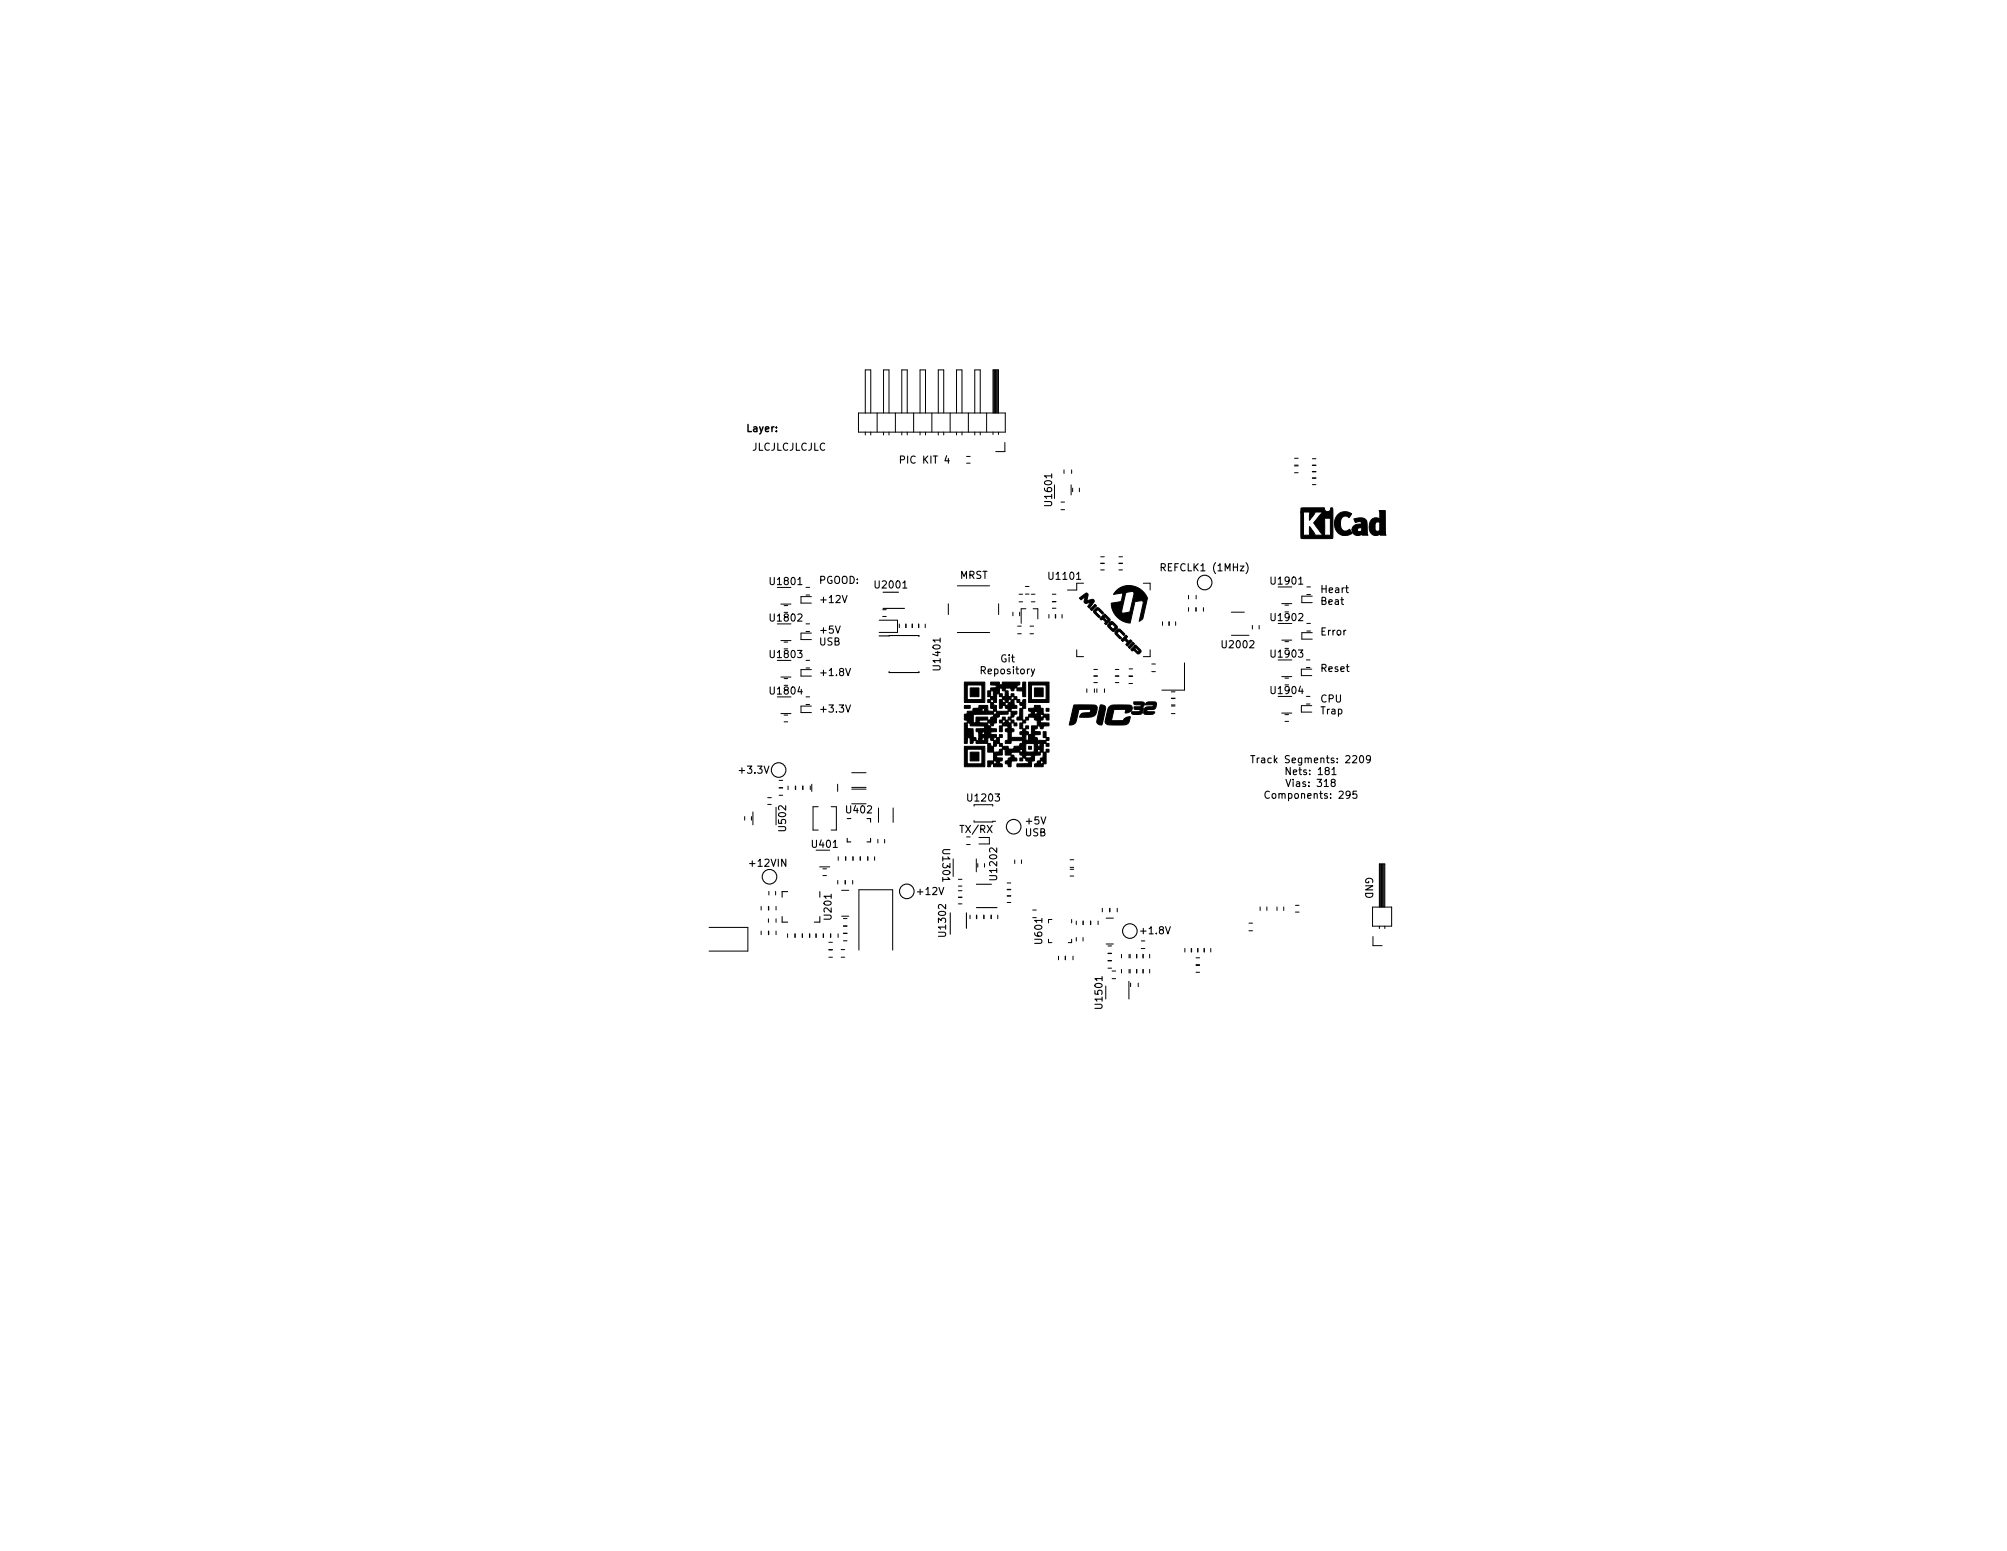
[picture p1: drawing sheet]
<svg xmlns="http://www.w3.org/2000/svg" width="279mm" height="216mm" viewBox="0 0 279 216" stroke-linecap="round" stroke-linejoin="round" font-family="sans-serif">
<defs><g id="words">
<g font-size="1.4">
<text x="104" y="60.1">Layer:</text>
<text x="104.6" y="62.7">JLCJLCJLCJLC</text>
<text x="125.7" y="64.5">PIC KIT 4</text>
<text x="146.5" y="70.2" transform="rotate(-90 146.5 70.2)">U1601</text>
<text x="107.4" y="81.4">U1801</text>
<text x="113.9" y="81.3">PGOOD:</text>
<text x="113.9" y="83.9">+12V</text>
<text x="122" y="81.9">U2001</text>
<text x="133.6" y="80.6">MRST</text>
<text x="146.2" y="80.7">U1101</text>
<text x="162" y="79.5">REFCLK1 (1MHz)</text>
<text x="177.1" y="81.4">U1901</text>
<text x="183.7" y="82.5">Heart</text>
<text x="107.4" y="86.5">U1802</text>
<text x="113.9" y="88.2">+5V</text>
<text x="113.9" y="89.8">USB</text>
<text x="177.1" y="86.4">U1902</text>
<text x="183.7" y="88.4">Error</text>
<text x="183.7" y="84.2">Beat</text>
<text x="107.4" y="91.6">U1803</text>
<text x="113.9" y="94.1">+1.8V</text>
<text x="130.9" y="93.1" transform="rotate(-90 130.9 93.1)">U1401</text>
<text x="136.6" y="93.8">Repository</text>
<text x="139.3" y="92.2">Git</text>
<text x="170.3" y="90.2">U2002</text>
<text x="177.1" y="91.5">U1903</text>
<text x="183.7" y="93.5">Reset</text>
<text x="107.4" y="96.7">U1804</text>
<text x="113.9" y="99.2">+3.3V</text>
<text x="177.1" y="96.6">U1904</text>
<text x="183.7" y="97.8">CPU</text>
<text x="183.7" y="99.4">Trap</text>
<text x="103.1" y="107.7">+3.3V</text>
<text x="175.1" y="106.2">Track Segments: 2209</text>
<text x="179.4" y="107.9">Nets: 181</text>
<text x="117.9" y="113.2">U402</text>
<text x="134.9" y="111.6">U1203</text>
<text x="176.7" y="111.2">Components: 295</text>
<text x="179.5" y="109.5">Vias: 318</text>
<text x="109.4" y="115.6" transform="rotate(-90 109.4 115.6)">U502</text>
<text x="113.1" y="118">U401</text>
<text x="131.2" y="118.4" transform="rotate(90 131.2 118.4)">U1301</text>
<text x="133.8" y="115.9">TX/RX</text>
<text x="142.7" y="116.4">USB</text>
<text x="142.9" y="114.8">+5V</text>
<text x="104.5" y="120.6">+12VIN</text>
<text x="127.8" y="124.6">+12V</text>
<text x="138.8" y="122.3" transform="rotate(-90 138.8 122.3)">U1202</text>
<text x="190.1" y="122" transform="rotate(90 190.1 122)">GND</text>
<text x="115.8" y="127.9" transform="rotate(-90 115.8 127.9)">U201</text>
<text x="131.7" y="130.2" transform="rotate(-90 131.7 130.2)">U1302</text>
<text x="145.1" y="131.3" transform="rotate(-90 145.1 131.3)">U601</text>
<text x="158.9" y="130">+1.8V</text>
<text x="153.5" y="140.2" transform="rotate(-90 153.5 140.2)">U1501</text>
</g>
</g></defs>
<g fill="none" stroke="#000" stroke-width=".15">
<path d="M116.3 87.1l.3 1 .4-1M117.3 82.9l.3 1 .3-1M117.7 93l.4 1 .3-1M117.7 98.1l.4 1 .3-1M122.4 88.5h5.5v.1M122.9 84.7h3M122.9 82.4h2.2M123.8 93.5v.1h4.1v-.1M117.9 116.7v.5h.5M117.9 113.9h.5M120.7 113.9h.5v.5M121.2 116.7v.5h-.5"/>
<path d="M174.1 105.2h.6M174.4 105.2v1M176.7 110.2a.47 .47 0 0 0-.6 .4 .47 .47 0 0 0 .4 .5l.2-.1M185.4 107.8h.6M188.9 110.1h-.5l-.1 .5 .2-.1 .3 .1 .1 .1v.3l-.2 .1-.4-.1M190.8 105.6l-.2 .2h-.3l-.1-.2 .1-.4h.3l.1 .1a.66 .66 0 0 1-.2 .9h-.2M108.9 127.6v.8h.8M109.7 124.1h-.8v.8M114.1 127.6v.8h-.7M114.1 124.1v.8M132.3 127.1v2.9M134.5 127.1v2.1"/>
<path d="M135.9 123.1h2.1M135.9 126.3h2.9"/>
<circle cx="167.7" cy="81.1" r="1.02"/>
<circle cx="108.4" cy="107.2" r="1.02"/>
<circle cx="141.1" cy="115.1" r="1.02"/>
<circle cx="107.1" cy="122" r="1.02"/>
<circle cx="126.2" cy="124.1" r="1.02"/>
<circle cx="157.3" cy="129.6" r="1.02"/>
</g>
<g fill="#000" stroke="#000" stroke-width=".14">
<path d="M181.1 70.7h3.3a.45 .45 0 0 0 .4 .5 .45 .45 0 0 0 .5-.5h.2l.1 .3v3.6l-.1 .4-4.4-.1v-3.6h.3a9.2 9.2 0 0 1 .1 2.9l-.1 .3h1l-.1-.3v-.9l.6 .8 .1 .4h2.3l-.1-2.4h-.9l.1 2.1-.1 .3h-.1l-1.3-1.7 1.3-1.5h-1.1l-.8 1.1 .1-1.1h-1.3zM186.3 71.6a1.45 1.45 0 0 1 1.9-.1l-.4 .5a.72 .72 0 0 0-.8-.1 .72 .72 0 0 0-.4 .8 .97 .97 0 0 0 .5 1.2h.5l.3-.2 .3 .5a1.51 1.51 0 0 1-1.8 .1 1.51 1.51 0 0 1-.6-1.7l.1-.5zM188.5 72.2a1.55 1.55 0 0 1 1.7 .3l.2 2h-.8v-.2a.83 .83 0 0 1-.9 .2 .83 .83 0 0 1-.5-.8h.7a.32 .32 0 0 0 .4 .3 .32 .32 0 0 0 .3-.3v-.2h-.2h-.3l-.2 .2h-.7a.88 .88 0 0 1 1.1-.8h.3a.46 .46 0 0 0-.3-.3 .46 .46 0 0 0-.5 .1h-.1zM192 71.1h.8l.1 3 .1 .4h-.9v-.2a.95 .95 0 0 1-1.1 .1 .95 .95 0 0 1-.4-1h.8a.42 .42 0 0 0 .1 .5 .42 .42 0 0 0 .6-.1v-1.1h-.1a.39 .39 0 0 0-.5 0 .39 .39 0 0 0-.1 .5v.2h-.8a1 1 0 0 1 1.2-1.3l.3 .1v-.9zM134.3 98.2h.8v.4h-.8zM135.1 95.8h1.2v1.2h-1.2zM134.3 94.9h2.8v2.9h-2.8v-2.4h.4v2h2v-2h-2.4zM134.3 99.4l.3-.1 .1-.3h.7l.1-.3h1.2l.1 .3h.1a.19 .19 0 0 0 .2-.2 .19 .19 0 0 0-.2-.2l-.2 .1h-1.2v-.1h.8v-.4h1.2v.8h.8l-.1-.4h-.3v-.8h-.4v-.4h.4v.4a.33 .33 0 0 1 .4 0 .33 .33 0 0 1 .1 .4h.3v.8h-.4v.4h-2.8v1.2h.4v-.8h1.6v.4l-1.2 .1v.3h1.2v.4a.36 .36 0 0 1 .4 .4l.8 .1v.3l-.8 .1v.3l.8 .1v.4a.34 .34 0 0 0-.4 .4 .3 .3 0 0 1-.4-.1 .3 .3 0 0 1-.1-.3h-.3v.8h-1.6v-.4l.4-.1v-.2h.4l.1 .2 .1 .1a.19 .19 0 0 0 .2-.2 .19 .19 0 0 0-.2-.2l-.2 .1h-.4v-.8h.4l.1 .2 .1 .1a.19 .19 0 0 0 .2-.2 .19 .19 0 0 0-.2-.2l-.2 .1h-.4v-.1l-.4-.1v-.3l1.2-.1v-.3l-2-.1-.1-.3-.3-.1-.1-.3-.3-.1zM137.9 94.9h1.2l.1 .4h.1h.2v-.4h2.5l-.1 .4-.3 .1v.4h-.4a.24 .24 0 0 1-.2 .4 .24 .24 0 0 1-.3-.2v-.2h-.7l-.1 .4h-.3l-.1-.4h-.3l-.1 .8h-.4v1.2h-.3l-.2-.4h-.3v-.4h.4v-.8h-.4v.8h-.4v-.8l.4-.1v-.3l.8-.1v-.3l-.8-.1zM139.1 97.4h.4a.34 .34 0 0 0 .4 .4v.4l-.3 .1-.1 .3h-.4zM139.5 99.8h.4v.4h-.4zM139.1 96.6h.4v.4h-.4z"/>
<path d="M139.9 96.2h.4l.1 .8h.4v-.4h.4v.4h-.4a.33 .33 0 0 1-.1 .4 .33 .33 0 0 1-.3 .1 .25 .25 0 0 1-.2 .3 .25 .25 0 0 1-.3-.3v-.1a.24 .24 0 0 1-.4-.1 .24 .24 0 0 1 .2-.3h.2zM141.2 97h.4v.4h-.4zM138.7 99h1.7l-.1-.3a.35 .35 0 0 1-.4-.5h.4a.42 .42 0 0 1 .4-.5l.1-.3h.4v.8h.4v.4h-.8l-.1 .4h-.3l-.1 .4h-1.1l-.1 .4h-.4v.8l-.4 .1a.25 .25 0 0 1-.2 .3 .25 .25 0 0 1-.2-.3h-.1a.25 .25 0 0 1-.3-.3 .25 .25 0 0 1 .3-.2 .42 .42 0 0 1 .5-.5 .34 .34 0 0 1 .4-.4zM143.2 98.6h.8v-.4h.8l.1 .4h.3v.8l-.4 .1 .1 .3h.3v-.4h.8v.8h-.3l-.1-.3-.4-.1v.4l-.3 .1-.1 .3h1.2v.4l-.8 .1v.2a.23 .23 0 0 1-.3 .1 .23 .23 0 0 1-.1-.3l-.4-.1v-.7l-.4-.1v-.4h-.8v.4h-.4v-.4h.4a.32 .32 0 0 1 0-.4 .32 .32 0 0 1 .4-.1v-.1h.4l.1 .2h.1a.19 .19 0 0 0 .2-.2 .19 .19 0 0 0-.2-.2l-.2 .2h-.4l-.1-.2h-.3zM141.6 95.8l.8-.1v-.8h.4v2.1h-.4v-.8h-.8zM144 95.8h1.2v1.2h-1.2zM145.6 98.6h.4v.4h-.4zM143.2 94.9h2.8v2.9h-2.8v-2.4h.4v2h2v-2h-2.4zM149.5 98.1l2.9 .1a.48 .48 0 0 1 .3 .7 1.02 1.02 0 0 1-1.3 .9h-1.1l.1-.3a.73 .73 0 0 1 .8-.3h.6l.1-.5-1.7 .1-.2 1a1.01 1.01 0 0 1-1.1 1.1zM150.3 83.3l1-.7a.48 .48 0 0 1 .1 .7l-.1 .3 .4-.1a.38 .38 0 0 1 .4-.1 .38 .38 0 0 1 .2 .4l-.6 .9-.3-.3 .5-.6-.8 .2a.48 .48 0 0 1-.1-.7l.1-.3-.4 .3a.22 .22 0 0 1-.3 .2 .22 .22 0 0 1-.1-.2zM151.8 84.8l.6-.7 .3 .2-.7 .7zM152.3 85l.4-.4 .3 .1 .6 .6v.1l-.1 .1-.6-.6-.3 .3 .6 .6a.28 .28 0 0 1-.3 .1 .28 .28 0 0 1-.2-.2l-.4-.4z"/>
<path d="M153.2 98.1a.57 .57 0 0 1 .7 .2 .57 .57 0 0 1-.1 .7l-.2 .9a1.33 1.33 0 0 1-.3 1 .57 .57 0 0 1-.6-.2 .57 .57 0 0 1 .1-.7zM153.5 85.8l.4 .4a.21 .21 0 0 0 .1 .2 .21 .21 0 0 0 .2-.1l-.4-.5-.2 .2-.1-.2 .3-.4 .7 .9v.1l-.2 .2h-.2v.2l-.1 .2-.2-.2 .1-.2-.2-.3-.2-.1-.2 .1-.2-.2zM154.2 87l.3-.3 .2 .2-.2 .3 .3 .2a.23 .23 0 0 0 .2 .2 .23 .23 0 0 0 .2-.3v-.1l-.3-.3h-.2l-.2-.2 .1-.2h.2l.4 .4a.55 .55 0 0 1 .3 .6l-.4 .4h-.2l-.7-.7zM155.2 88l.4-.4h.3l.7 .7-.1 .2-.7-.6-.2 .2-.1 .1 .6 .6a.3 .3 0 0 1-.3 .1 .3 .3 0 0 1-.2-.3l-.4-.4zM154.5 98.3l.4-.2h2a.54 .54 0 0 1 .7 .4 .54 .54 0 0 1-.4 .7h-.6l.1-.5-1.6 .1-.4 1.5h1.7a.9 .9 0 0 1 1-.5 1.02 1.02 0 0 1-1.3 1.1h-.9a1.4 1.4 0 0 1-1.3-.3l.3-1.9zM157.1 90.1l.6-.7 .2 .2-.6 .7zM156.1 89.1l.7-.7 .2 .2-.3 .3 .4 .4 .3-.3 .2 .3-.7 .6-.2-.2 .3-.2-.4-.4-.3 .2zM158.1 89.8l.7 .7v.3l-.2 .2h-.3l-.5-.5-.2 .1-.2-.2 .5-.5 .2 .2-.1 .2 .2 .2a.2 .2 0 0 0 .1 .2 .2 .2 0 0 0 .3-.1l-.7-.7zM157.8 97.7h1.1a.36 .36 0 0 1 .4 .3 .36 .36 0 0 1-.3 .4 .69 .69 0 0 1 0 .8 .69 .69 0 0 1-.8 .3l-.5-.1-.2-.2v-.1l1.2-.1v-.2h-.3a.33 .33 0 0 1-.4 0 .33 .33 0 0 1-.1-.4h1v-.3h-.7a.3 .3 0 0 1-.3-.1 .3 .3 0 0 1-.1-.3zM155.4 82.2l.6-.4 .7 .7-.6 2.6a.37 .37 0 0 0 .7 .2h.1a.37 .37 0 0 0 .4-.1 .37 .37 0 0 0 .1-.4l.4-2.3-.2-.2-.9 .2-.6-.7a2.77 2.77 0 0 1 3.6 1.4l-.6 2.9-.5 .4 .6-2.7a.35 .35 0 0 0-.6-.1l-.6 .1-.7 2.9a2.84 2.84 0 0 1-2.6-2.7l.7-.1a.62 .62 0 0 0 .8-.6l.1-.8-1.3 .2zM159.6 97.8h.1a1.8 1.8 0 0 1 1.3 0 .68 .68 0 0 1-.1 .8 .68 .68 0 0 1-.8 .2h-.4l-.1 .2 1.1 .1a.36 .36 0 0 1-.5 .4h-.2a.76 .76 0 0 1-.8-.2 .7 .7 0 0 1 .2-.7 .7 .7 0 0 1 .7-.2h.4l.1-.3h-1.2zM134.3 100.6h.4v.8l.8 .1v1.1l.3 .1 .1 .1v.3h-.3a.35 .35 0 0 1-.5 .4l-.1-.8h-.3v.8h-.4z"/>
<path d="M135.1 104.7h1.2v1.2h-1.2zM134.3 103.9h2.8v2.8h-2.8v-2.4h.4v2h2v-2h-2.4zM137.5 103.5h.3l.2 .4h.3v.8h-.8zM137.5 105.9h.8v.4l-.4 .1v.3h-.4zM139.1 103.5h.4v.4h-.4zM139.1 102.3h.4v.4h-.4v.8l-.3 .1-.1 .3h-.4v-.8l.3-.1a.38 .38 0 0 1 .5-.4zM139.1 101h.4v.9h-.4zM139.1 100.2h.4v.4h-.4zM139.6 100.7a.34 .34 0 0 0 .4-.5 .3 .3 0 0 1 .3 .1 .3 .3 0 0 1 .1 .3h.4v.8h.2a.21 .21 0 0 1 .2 .3 .21 .21 0 0 1-.2 .2h-.2v.7h1.6l-.1-.3a.25 .25 0 0 1-.3-.2 .25 .25 0 0 1 .3-.3 .25 .25 0 0 1 .3-.4 .25 .25 0 0 1 .2 .4h.1a.24 .24 0 0 1 .3 .2 .24 .24 0 0 1-.2 .3h-.2v.7h.4v-.7l.4-.1v-1.2h.8v.4l-.4 .1v.3l.8 .1v.4h-.8v.3a.36 .36 0 0 1 .4 .4l1.2 .1v.4h-.4v1.2h-.4v.4h-.8v.8h-.4v.8h-2v-.4h1.6v-.3a.37 .37 0 0 1-.5-.5h.9v-.4h-.8v.4h-.4v-.3a.35 .35 0 0 1-.4-.5h.3l.1-.2a.19 .19 0 0 0-.2-.2 .19 .19 0 0 0-.2 .2v.2h-1.2l-.1 .4h-.8v-.8h-.4v.8h-.8v.4h.8v.4a.24 .24 0 0 0-.3 .1 .24 .24 0 0 0 0 .3l.3 .1v.3h-1.2v-.4h.3l.1-.2-.1-.1-.3-.1v-1.2h.8l.1-.4h.3v-.4h.8l.1 .4h2.4v.3l.1 .1h1.1v-.3h.4l.1 .3h.3a.23 .23 0 0 0 0-.3 .23 .23 0 0 0-.4 0h-.4v-.8h.4l.1 .3h.1a.19 .19 0 0 0 .2-.2 .19 .19 0 0 0-.2-.2l-.2 .1h-.4v-.1h-1.2v.8h-1.7l.1-.4h.7l.1-.4a.33 .33 0 0 0 .4-.4h-1.6l-.1 .4h-.8l.1-.4 .3-.1v-1.1h-.2a.23 .23 0 0 1-.2-.3 .23 .23 0 0 1 .4-.2v-.3l-.8-.1zM140.8 99h.8l-.1 .4a.34 .34 0 0 0-.4 .4l-.3 .1v.3h-.5v-.4h.5zM140.8 100.2h.4v.4h-.4zM140.8 105.1h.3a.35 .35 0 0 0 .5 .5v.3h-.8l-.1 .8h-.3a.34 .34 0 0 0-.4-.4 .3 .3 0 0 1 0-.4 .3 .3 0 0 1 .3-.1 .34 .34 0 0 1 .4-.4z"/>
<path d="M141.6 97.4h.4v.4l.3-.1 .1-.3h.4v1.2h-.4v1.6h-.8v-.4h.3l.1-1.2h.4v-.3a.38 .38 0 0 1-.5-.5h-.3zM141.2 100.6h.4v.4h-.4zM142 105.5h.4v.4h-.4zM142 100.6h.4v.8h-.4zM142.4 100.2h.4v.4h-.4zM142.8 101h.4v.4h-.4zM143.2 103.9h.4v.4h-.4zM145.2 101.9h.4v.8h-.4zM145.2 104.7h.4v1.6h-.4v.4h-1.2v-.4h.3l.1-.2h.4l.1 .2h.3a.25 .25 0 0 0 0-.3 .25 .25 0 0 0-.4 0v.1h-.4l.1-.2a.3 .3 0 0 0 .3 0 .3 .3 0 0 0 .1-.4h.3zM145.6 104.3h.4v.4h-.4zM145.6 103.5h.4v.4h-.4zM145.6 102.7h.4v.4h-.4z"/>
</g>
<g fill="none" stroke="#000" stroke-width=".14">
<path d="M119.5 57.5h20.4v2.7h-20.4zM120.5 57.5v-6h.7v6M122.1 57.5v2.7M123 57.5v-6h.8v6M124.6 57.5v2.7M125.5 57.5v-6h.8v6M127.2 57.5v2.7M128.1 57.5v-6h.7v6M129.7 57.5v2.7M130.6 57.5v-6h.8v6M132.3 57.5v2.7M133.2 57.5v-6h.7v6"/>
<path d="M134.8 57.5v2.7M135.7 57.5v-6h.8v6M137.3 57.5v2.7M138.2 57.5v-6h.8v6M138.3 51.5v6M138.5 51.5v6M138.6 51.5v6M138.7 51.5v6M138.8 51.5v6M138.9 51.5v6M120.5 60.2v.3M121.2 60.2v.3"/>
<path d="M123 60.2v.3M123.8 60.2v.3M125.5 60.2v.3M126.3 60.2v.3M128.1 60.2v.3M128.8 60.2v.3M130.6 60.2v.3M131.4 60.2v.3M133.2 60.2v.3M133.9 60.2v.3M134.6 64.5h.5M134.6 63.5h.5"/>
<path d="M135.7 60.2v.3M136.5 60.2v.3M138.2 60.2v.3M139 60.2v.3M139.9 61.6v1.3h-1.3M147.7 69.9h.5M147.7 70.9h.5M148.1 65.4v.5M149.1 67.5v1.4M149.2 65.4v.5M149.3 67.9v.5M150.3 67.9v.5"/>
<path d="M153.2 78.4h.5M153.2 77.5h.5M153.2 79.3h.5M155.8 78.4h.5M155.8 77.5h.5M155.8 79.3h.5M180.2 64.7h.5M180.2 65.8h.5M180.2 64.9h.5M180.2 63.8h.5M182.7 67.5h.5M182.7 66.5h.5"/>
<path d="M182.7 66.6h.5M182.7 65.6h.5M182.7 64.7h.5M182.7 63.9h.5M182.7 64.8h.5M182.7 65.7h.5M108.7 99.3h1.4M108.7 94.2h1.4M108.7 89.2h1.4M108.7 84.1h1.4M109.2 84.3h.5M109.2 99.5h.5"/>
<path d="M109.2 94.5h.5M109.2 89.4h.5M112.2 97h.5M112.2 98.1h.5M112.2 91.9h.5M112.2 93h.5M112.2 86.8h.5M112.2 87.9h.5M112.2 81.8h.5M112.2 82.8h.5M113 83.1h-1.5v.9h1.5M113 88.1h-1.5v.9h1.5"/>
<path d="M113 93.2h-1.5v.9h1.5M113 98.3h-1.5v.9h1.5M122.4 86.3h2.5v1.7h-2.5M122.9 84.9h.5M122.9 85.8h.5M125.2 86.9v.5M126.1 86.9v.5M127 86.9v.5M127.9 86.9v.5M128.8 86.9v.5M132 84v1.5M133.3 88h4.5"/>
<path d="M133.3 81.5h4.5M139 84v1.5M141 85.2v.5M141.7 88.2h.5M141.7 87.2h.5M141.9 83.8h.5M141.9 82.7h.5M141.9 85.2v.5M142.8 81.6h.5M142.8 82.7h.5M142.8 84.7h-.6v2.1M143.4 88.2h.5"/>
<path d="M143.4 87.2h.5M143.6 83.8h.5M143.6 82.7h.5M143.8 84.7h.7v1.4M146 85.5v.5M146.5 84.7h.5M146.5 83.7h.5M146.5 83.8h.5M146.5 82.7h.5M146.9 85.5v.5M147 85.5v.5M147.9 85.5v.5"/>
<path d="M149.9 90.5v.9h.9M150.8 81.2h-.9v.9h-1.3M151.3 95.9v.5M152.3 94.1h.5M152.3 93.2h.5M152.3 95h.5M152.4 95.9v.5M152.7 95.9v.5M153.8 95.9v.5M155.3 94.1h.5M155.3 93.2h.5M155.3 95h.5"/>
<path d="M157.2 95.1h.5M157.2 94.1h.5M157.2 94.2h.5M157.2 93.1h.5M159.2 81.2h.9v.9M160.1 90.5v.9h-.9M160.3 93.5h.5M160.3 92.4h.5M161.8 86.6v.5M162.7 86.6v.5M162.8 86.6v.5M163.1 99.3h.5"/>
<path d="M163.1 98.3h.5M163.1 97.2h.5M163.1 98.1h.5M163.1 96.3h.5M163.7 86.6v.5M164.9 92.3v3.8h-3.2M165.5 82.9v.5M165.5 84.6v.5M166.5 84.6v.5M166.5 82.9v.5M167.5 84.6v.5M171.4 85.2h1.8"/>
<path d="M171.4 88.4h2.5M174.3 87.1v.5M175.3 87.1v.5M178.4 99.3h1.4M178.4 94.2h1.4M178.4 89.1h1.4M178.4 84h1.4M178.9 99.5h.5M178.9 94.4h.5M178.9 89.3h.5M178.9 84.2h.5M181.9 96.9h.5"/>
<path d="M181.9 98h.5M181.9 91.9h.5M181.9 92.9h.5M181.9 86.8h.5M181.9 87.8h.5M181.9 81.7h.5M181.9 82.8h.5M182.6 93.1h-1.4v.9h1.4M182.6 98.2h-1.4v.9h1.4M182.7 83h-1.5v.9h1.5M182.7 88.1h-1.5v.9h1.5M103.7 113.7v.5"/>
<path d="M104.6 113.7v.5M104.8 113v1.8M106.9 112h.5M106.9 111h.5M108 112.4v2.4M108.5 108.6h.5M108.5 109.7h.5M108.5 109.6h.5M108.5 110.7h.5M109.2 100.5h.5M109.7 109.4v.5M110.7 109.4v.5"/>
<path d="M110.8 109.4v.5M111.7 109.4v.5M111.8 109.4v.5M112.8 109.4v.5M113 109.2v1M113.9 112.3h-.7v3.2h.7M115.7 112.3h.7v3.2h-.7M116.6 109.2v1M116.7 119.3v.5M117.7 119.3v.5M117.8 119.3v.5M118.6 107.6h2"/>
<path d="M118.6 109.6h2M118.6 109.9h2M118.7 119.3v.5M118.8 119.3v.5M119.7 119.3v.5M119.8 119.3v.5M120.8 119.3v.5M121.8 119.3v.5M122.2 116.8v.5M122.3 112.5v2M123.2 116.8v.5M124.3 112.5v2"/>
<path d="M132.7 119.6v2.4M134.6 116.5h.5M134.6 117.6h.5M135.6 112.2v-.2h2.6v.2M135.6 114.2v.2h2.6v-.1h.4M135.9 119.6v1.8M136.3 116.6h1.4v.9h-1.4M141.3 119.7v.5M142.2 119.7v.5M149 119.7h.5M178.9 100.4h.5M98.7 129.1h5.4v3.3h-5.4"/>
<path d="M106 126.2v.5M106 129.6v.5M107 126.2v.5M107 127.9v.5M107 129.6v.5M107 124.1v.5M108 124.1v.5M108 126.2v.5M108 127.9v.5M108 129.6v.5M109.6 130v.5M110.7 130v.5"/>
<path d="M111.7 130v.5M112.7 130v.5M113.6 130v.5M114.1 120.7h1.4M114.6 121.9h.5M114.6 120.9h.5M114.6 130v.5M115.4 131.2h.5M115.4 132.2h.5M115.4 133.2h.5M115.6 130v.5M115.7 130v.5"/>
<path d="M116.6 122.6v.5M116.7 130v.5M117.1 133.2h.5M117.1 132.2h.5M117.2 127.5h1M117.2 123.9h1M117.4 127.9h.5M117.4 128.9h.5M117.4 129.9h.5M117.4 131h.5M117.6 122.6v.5M117.7 122.6v.5"/>
<path d="M118.7 122.6v.5M119.6 132.3v-8.4h4.7v8.4M133.4 122.4h.5M133.4 123.3h.5M133.4 124.9h.5M133.4 124h.5M133.4 125.8h.5M135 127.4v.5M135.9 127.4v.5M136 127.4v.5M136.1 120.2v.5M136.9 127.4v.5"/>
<path d="M137 127.4v.5M137.1 120.2v.5M138 127.4v.5M138.9 127.4v.5M140.2 123.8h.5M140.2 122.9h.5M140.2 124.7h.5M140.2 125.6h.5M143.8 126.7h.5M146 130.7v.5h.4M146.4 128h-.4v.5M147.4 133.1v.5"/>
<path d="M148.3 133.1v.5M149 120.7h.5M149 121.9h.5M149 121h.5M149.2 128v.5M149.2 130.7v.5h-.5M149.4 133.1v.5M149.8 128.2v.5M149.8 130.5v.5M150.8 128.2v.5M150.8 130.5v.5M151.8 128.2v.5"/>
<path d="M151.9 128.2v.5M152.9 128.2v.5M153.5 126.4v.5M154 131.4h1M154 127.8h1M154.2 133.7h.5M154.2 134.8h.5M154.2 132.7h.5M154.2 133.8h.5M154.2 131.7h.5M154.5 126.4v.5M154.8 135.2h.5"/>
<path d="M154.8 136.2h.5M155.5 126.4v.5M156.1 132.8v.5M156.1 134.9v.5M157.2 136.6v2.5M157.2 132.8v.5M157.2 134.9v.5M157.3 132.8v.5M157.3 134.9v.5M157.4 136.8v.5M158.2 132.8v.5M158.2 134.9v.5"/>
<path d="M158.3 132.8v.5M158.3 134.9v.5M158.5 136.8v.5M158.9 131h.5M158.9 132h.5M159.1 132.8v.5M159.1 134.9v.5M159.2 132.8v.5M159.2 134.9v.5M160 132.8v.5M160 134.9v.5M164.9 132v.5"/>
<path d="M165.8 132v.5M165.9 132v.5M166.5 134.4h.5M166.5 133.3h.5M166.5 134.3h.5M166.5 135.3h.5M166.7 132v.5M166.8 132v.5M167.6 132v.5M167.7 132v.5M168.6 132v.5M173.9 129.6h.5"/>
<path d="M173.9 128.5h.5M175.4 126.2v.5M176.4 126.2v.5M177.8 126.2v.5M178.7 126.2v.5M180.3 127h.5M180.3 126h.5M191.1 126.3h2.6v2.6h-2.6zM191.1 130.4v1.2h1.3M192 126.3v-6h.8v6M192 128.9v.4M192.1 120.3v6"/>
<path d="M192.2 120.3v6M192.3 120.3v6M192.4 120.3v6M192.6 120.3v6M192.7 120.3v6M192.8 128.9v.4"/>
</g>
<use href="#words"/>
</svg>
